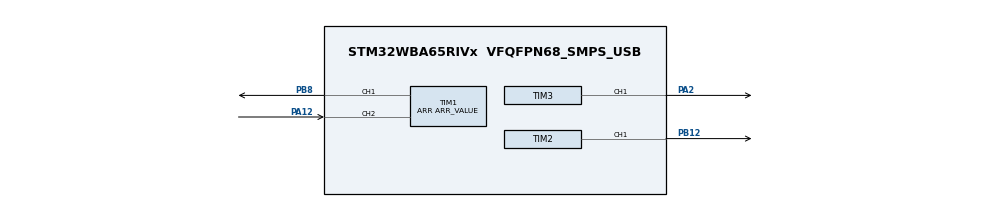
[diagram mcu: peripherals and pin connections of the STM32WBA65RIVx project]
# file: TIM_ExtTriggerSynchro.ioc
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CORTEX_M33_NS.userName=CORTEX_M33
Mcu.Family=STM32WBA
Mcu.Name=STM32WBA65RIVx
Mcu.Package=VFQFPN68_SMPS_USB
NVIC.PriorityGroup=NVIC_PRIORITYGROUP_4
OSC_IN.Mode=HSE-External-Oscillator
OSC_IN.PinAttribute=CortexM33
OSC_IN.Signal=RCC_OSC_IN
OSC_OUT.Mode=HSE-External-Oscillator
OSC_OUT.PinAttribute=CortexM33
OSC_OUT.Signal=RCC_OSC_OUT
PA12.GPIO_PuPd=GPIO_PULLDOWN
PA12.GPIO_Speed=GPIO_SPEED_FREQ_HIGH
PA12.PinAttribute=CortexM33
PA12.Signal=S_TIM1_CH2
PA2.GPIO_PuPd=GPIO_PULLDOWN
PA2.GPIO_Speed=GPIO_SPEED_FREQ_HIGH
PA2.PinAttribute=CortexM33
PA2.Signal=S_TIM3_CH1
PB12.GPIO_PuPd=GPIO_PULLDOWN
PB12.GPIO_Speed=GPIO_SPEED_FREQ_HIGH
PB12.PinAttribute=CortexM33
PB12.Signal=S_TIM2_CH1
PB8.GPIO_PuPd=GPIO_PULLDOWN
PB8.GPIO_Speed=GPIO_SPEED_FREQ_HIGH
PB8.PinAttribute=CortexM33
PB8.Signal=S_TIM1_CH1
ProjectManager.HeapSize=0x200
ProjectManager.StackSize=0x400
ProjectManager.TargetToolchain=EWARM V9.20
RCC.ADCFreq_Value=100000000
RCC.AHB5CLKDivider=DIV4
RCC.AHBFreq_Value=100000000
RCC.APB1Freq_Value=100000000
RCC.APB1TimFreq_Value=100000000
RCC.APB2Freq_Value=100000000
RCC.APB2TimFreq_Value=100000000
RCC.CortexFreq_Value=12500000
RCC.HCLKFreq_Value=100000000
RCC.HSE_VALUE=32000000
RCC.HSI_VALUE=16000000
RCC.LSE_VALUE=32768
RCC.LSI1_VALUE=32000
RCC.LSI2_VALUE=32000
RCC.PLLFRACN=4096
RCC.PLLM=2
RCC.PLLN=12
RCC.PLLSourceVirtual=RCC_PLLSOURCE_HSE
RCC.SYSCLKFreq_VALUE=100000000
RCC.SYSCLKSourceVirtual=RCC_SYSCLKSOURCE_PLLCLK
RCC.VCOOutputFreq_Value=200000000
SH.S_TIM1_CH1.0=TIM1_CH1,Output Compare1 CH1
SH.S_TIM1_CH2.0=TIM1_CH2,TriggerSource_TI2FP2
SH.S_TIM2_CH1.0=TIM2_CH1,Output Compare1 CH1
SH.S_TIM3_CH1.0=TIM3_CH1,Output Compare1 CH1
TIM1.Channel-Output\ Compare1\ CH1=TIM_CHANNEL_1
TIM1.OCMode_1=TIM_OCMODE_TOGGLE
TIM1.PeriodNoDither=ARR_VALUE
TIM1.Prescaler=MASTER_PRESCALER_VALUE
TIM1.TIM_MasterOutputTrigger=TIM_TRGO_ENABLE
TIM1.TIM_MasterOutputTrigger2=TIM_TRGO2_ENABLE
TIM1.TIM_MasterSlaveMode=TIM_MASTERSLAVEMODE_ENABLE
TIM2.Channel-Output\ Compare1\ CH1=TIM_CHANNEL_1
TIM2.OCMode_1=TIM_OCMODE_TOGGLE
TIM2.PeriodNoDither=ARR_VALUE
TIM2.Prescaler=SLAVE_MASTER_PRESCALER_VALUE
TIM2.TIM_MasterOutputTrigger=TIM_TRGO_ENABLE
TIM2.TIM_MasterSlaveMode=TIM_MASTERSLAVEMODE_ENABLE
TIM3.Channel-Output\ Compare1\ CH1=TIM_CHANNEL_1
TIM3.OCMode_1=TIM_OCMODE_TOGGLE
TIM3.PeriodNoDither=ARR_VALUE
TIM3.Prescaler=SLAVE_PRESCALER_VALUE
VP_CORTEX_M33_NS_VS_Hclk.Mode=Hclk_Mode
VP_ICACHE_VS_ICACHE.Mode=DirectMappedCache
VP_PWR_VS_SECSignals.Mode=Security/Privilege
VP_TIM1_VS_ControllerModeGated.Mode=Gated Mode
VP_TIM2_VS_ClockSourceITR.Mode=TriggerSource_ITR0
VP_TIM2_VS_ControllerModeGated.Mode=Gated Mode
VP_TIM3_VS_ClockSourceITR.Mode=TriggerSource_ITR1
VP_TIM3_VS_ControllerModeGated.Mode=Gated Mode
board=custom

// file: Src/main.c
/* USER CODE BEGIN Header */
/**
  ******************************************************************************
  * @file    TIM/TIM_ExtTriggerSynchro/Src/main.c
  * @author  MCD Application Team
  * @brief   This sample code shows how to synchronize TIM peripherals in cascade
  *          mode with an external trigger.
  ******************************************************************************
  * @attention
  *
  * Copyright (c) 2024 STMicroelectronics.
  * All rights reserved.
  *
  * This software is licensed under terms that can be found in the LICENSE file
  * in the root directory of this software component.
  * If no LICENSE file comes with this software, it is provided AS-IS.
  *
  ******************************************************************************
  */
/* USER CODE END Header */
#include "main.h"

TIM_HandleTypeDef htim1;
TIM_HandleTypeDef htim2;
TIM_HandleTypeDef htim3;

void SystemClock_Config(void);
static void MX_GPIO_Init(void);
static void MX_ICACHE_Init(void);
static void MX_TIM1_Init(void);
static void MX_TIM2_Init(void);
static void MX_TIM3_Init(void);

int main(void)
{

  /* USER CODE BEGIN 1 */
  /* STM32WBAxx HAL library initialization:
       - Systick timer is configured by default as source of time base, but user
             can eventually implement his proper time base source (a general purpose
             timer for example or other time source), keeping in mind that Time base
             duration should be kept 1ms since PPP_TIMEOUT_VALUEs are defined and
             handled in milliseconds basis.
       - Set NVIC Group Priority to 4
       - Low Level Initialization
     */
  /* USER CODE END 1 */

  /* MCU Configuration--------------------------------------------------------*/

  /* Reset of all peripherals, Initializes the Flash interface and the Systick. */
  HAL_Init();

  /* Configure the system clock */
  SystemClock_Config();

  /* Initialize all configured peripherals */
  MX_GPIO_Init();
  MX_ICACHE_Init();
  MX_TIM1_Init();
  MX_TIM2_Init();
  MX_TIM3_Init();
  /* USER CODE BEGIN 2 */

  /* Start TIM1 xxxxxxxxxxxxxxxxxxxxxxxxxxxxxxxxxxxxxxxxxxxxxxxxxxxxxxxx */
  /* Start Channel2 in Input Capture */
  if(HAL_TIM_IC_Start(&htim1, TIM_CHANNEL_2) != HAL_OK)
  {
    /* Start Error */
    Error_Handler();
  }
  /* Start the Output Compare */
  if(HAL_TIM_OC_Start(&htim1, TIM_CHANNEL_1) != HAL_OK)
  {
    /* Start Error */
    Error_Handler();
  }

  /* Start TIM2 xxxxxxxxxxxxxxxxxxxxxxxxxxxxxxxxxxxxxxxxxxxxxxxxxxxxxxxx */
  /* Start the Output Compare */
  if(HAL_TIM_OC_Start(&htim2, TIM_CHANNEL_1) != HAL_OK)
  {
    /* Start Error */
    Error_Handler();
  }

  /* Start TIM3 xxxxxxxxxxxxxxxxxxxxxxxxxxxxxxxxxxxxxxxxxxxxxxxxxxxxxxxx */
  /* Start the Output Compare */
  if(HAL_TIM_OC_Start(&htim3, TIM_CHANNEL_1) != HAL_OK)
  {
    /* Start Error */
    Error_Handler();
  }

  /* USER CODE END 2 */

  /* Infinite loop */
  while (1)
  {

  }
}

void SystemClock_Config(void)
{
  RCC_OscInitTypeDef RCC_OscInitStruct = {0};
  RCC_ClkInitTypeDef RCC_ClkInitStruct = {0};

  /** Supply configuration update enable
  */
  HAL_PWREx_ConfigSupply(PWR_LDO_SUPPLY);

  /** Configure the main internal regulator output voltage
  */
  if (HAL_PWREx_ControlVoltageScaling(PWR_REGULATOR_VOLTAGE_SCALE1) != HAL_OK)
  {
    Error_Handler();
  }

  /** Initializes the CPU, AHB and APB busses clocks
  */
  RCC_OscInitStruct.OscillatorType = RCC_OSCILLATORTYPE_HSE;
  RCC_OscInitStruct.HSEState = RCC_HSE_ON;
  RCC_OscInitStruct.HSEDiv = RCC_HSE_DIV1;
  RCC_OscInitStruct.PLL1.PLLState = RCC_PLL_ON;
  RCC_OscInitStruct.PLL1.PLLSource = RCC_PLLSOURCE_HSE;
  RCC_OscInitStruct.PLL1.PLLM = 2;
  RCC_OscInitStruct.PLL1.PLLN = 12;
  RCC_OscInitStruct.PLL1.PLLP = 2;
  RCC_OscInitStruct.PLL1.PLLQ = 2;
  RCC_OscInitStruct.PLL1.PLLR = 2;
  RCC_OscInitStruct.PLL1.PLLFractional = 4096;
  if (HAL_RCC_OscConfig(&RCC_OscInitStruct) != HAL_OK)
  {
    Error_Handler();
  }

  /** Initializes the CPU, AHB and APB busses clocks
  */
  RCC_ClkInitStruct.ClockType = RCC_CLOCKTYPE_HCLK|RCC_CLOCKTYPE_SYSCLK
                              |RCC_CLOCKTYPE_PCLK1|RCC_CLOCKTYPE_PCLK2
                              |RCC_CLOCKTYPE_PCLK7|RCC_CLOCKTYPE_HCLK5;
  RCC_ClkInitStruct.SYSCLKSource = RCC_SYSCLKSOURCE_PLLCLK;
  RCC_ClkInitStruct.AHBCLKDivider = RCC_SYSCLK_DIV1;
  RCC_ClkInitStruct.APB1CLKDivider = RCC_HCLK_DIV1;
  RCC_ClkInitStruct.APB2CLKDivider = RCC_HCLK_DIV1;
  RCC_ClkInitStruct.APB7CLKDivider = RCC_HCLK_DIV1;
  RCC_ClkInitStruct.AHB5_PLL1_CLKDivider = RCC_SYSCLK_PLL1_DIV4;
  RCC_ClkInitStruct.AHB5_HSEHSI_CLKDivider = RCC_SYSCLK_HSEHSI_DIV1;

  if (HAL_RCC_ClockConfig(&RCC_ClkInitStruct, FLASH_LATENCY_3) != HAL_OK)
  {
    Error_Handler();
  }
}

static void MX_ICACHE_Init(void)
{

  /** Enable instruction cache in 1-way (direct mapped cache)
  */
  if (HAL_ICACHE_ConfigAssociativityMode(ICACHE_1WAY) != HAL_OK)
  {
    Error_Handler();
  }
  if (HAL_ICACHE_Enable() != HAL_OK)
  {
    Error_Handler();
  }

}

static void MX_TIM1_Init(void)
{

  TIM_SlaveConfigTypeDef sSlaveConfig = {0};
  TIM_MasterConfigTypeDef sMasterConfig = {0};
  TIM_OC_InitTypeDef sConfigOC = {0};
  TIM_BreakDeadTimeConfigTypeDef sBreakDeadTimeConfig = {0};

  htim1.Instance = TIM1;
  htim1.Init.Prescaler = MASTER_PRESCALER_VALUE;
  htim1.Init.CounterMode = TIM_COUNTERMODE_UP;
  htim1.Init.Period = ARR_VALUE;
  htim1.Init.ClockDivision = TIM_CLOCKDIVISION_DIV1;
  htim1.Init.RepetitionCounter = 0;
  htim1.Init.AutoReloadPreload = TIM_AUTORELOAD_PRELOAD_DISABLE;
  if (HAL_TIM_Base_Init(&htim1) != HAL_OK)
  {
    Error_Handler();
  }
  if (HAL_TIM_OC_Init(&htim1) != HAL_OK)
  {
    Error_Handler();
  }
  sSlaveConfig.SlaveMode = TIM_SLAVEMODE_GATED;
  sSlaveConfig.InputTrigger = TIM_TS_TI2FP2;
  sSlaveConfig.TriggerPolarity = TIM_TRIGGERPOLARITY_RISING;
  sSlaveConfig.TriggerFilter = 0;
  if (HAL_TIM_SlaveConfigSynchro(&htim1, &sSlaveConfig) != HAL_OK)
  {
    Error_Handler();
  }
  sMasterConfig.MasterOutputTrigger = TIM_TRGO_ENABLE;
  sMasterConfig.MasterOutputTrigger2 = TIM_TRGO2_ENABLE;
  sMasterConfig.MasterSlaveMode = TIM_MASTERSLAVEMODE_ENABLE;
  if (HAL_TIMEx_MasterConfigSynchronization(&htim1, &sMasterConfig) != HAL_OK)
  {
    Error_Handler();
  }
  sConfigOC.OCMode = TIM_OCMODE_TOGGLE;
  sConfigOC.Pulse = 0;
  sConfigOC.OCPolarity = TIM_OCPOLARITY_HIGH;
  sConfigOC.OCNPolarity = TIM_OCNPOLARITY_HIGH;
  sConfigOC.OCFastMode = TIM_OCFAST_DISABLE;
  sConfigOC.OCIdleState = TIM_OCIDLESTATE_RESET;
  sConfigOC.OCNIdleState = TIM_OCNIDLESTATE_RESET;
  if (HAL_TIM_OC_ConfigChannel(&htim1, &sConfigOC, TIM_CHANNEL_1) != HAL_OK)
  {
    Error_Handler();
  }
  sBreakDeadTimeConfig.OffStateRunMode = TIM_OSSR_DISABLE;
  sBreakDeadTimeConfig.OffStateIDLEMode = TIM_OSSI_DISABLE;
  sBreakDeadTimeConfig.LockLevel = TIM_LOCKLEVEL_OFF;
  sBreakDeadTimeConfig.DeadTime = 0;
  sBreakDeadTimeConfig.BreakState = TIM_BREAK_DISABLE;
  sBreakDeadTimeConfig.BreakPolarity = TIM_BREAKPOLARITY_HIGH;
  sBreakDeadTimeConfig.BreakFilter = 0;
  sBreakDeadTimeConfig.BreakAFMode = TIM_BREAK_AFMODE_INPUT;
  sBreakDeadTimeConfig.Break2State = TIM_BREAK2_DISABLE;
  sBreakDeadTimeConfig.Break2Polarity = TIM_BREAK2POLARITY_HIGH;
  sBreakDeadTimeConfig.Break2Filter = 0;
  sBreakDeadTimeConfig.Break2AFMode = TIM_BREAK_AFMODE_INPUT;
  sBreakDeadTimeConfig.AutomaticOutput = TIM_AUTOMATICOUTPUT_DISABLE;
  if (HAL_TIMEx_ConfigBreakDeadTime(&htim1, &sBreakDeadTimeConfig) != HAL_OK)
  {
    Error_Handler();
  }
  HAL_TIM_MspPostInit(&htim1);

}

static void MX_TIM2_Init(void)
{

  TIM_SlaveConfigTypeDef sSlaveConfig = {0};
  TIM_MasterConfigTypeDef sMasterConfig = {0};
  TIM_OC_InitTypeDef sConfigOC = {0};

  htim2.Instance = TIM2;
  htim2.Init.Prescaler = SLAVE_MASTER_PRESCALER_VALUE;
  htim2.Init.CounterMode = TIM_COUNTERMODE_UP;
  htim2.Init.Period = ARR_VALUE;
  htim2.Init.ClockDivision = TIM_CLOCKDIVISION_DIV1;
  htim2.Init.AutoReloadPreload = TIM_AUTORELOAD_PRELOAD_DISABLE;
  if (HAL_TIM_Base_Init(&htim2) != HAL_OK)
  {
    Error_Handler();
  }
  if (HAL_TIM_OC_Init(&htim2) != HAL_OK)
  {
    Error_Handler();
  }
  sSlaveConfig.SlaveMode = TIM_SLAVEMODE_GATED;
  sSlaveConfig.InputTrigger = TIM_TS_ITR0;
  if (HAL_TIM_SlaveConfigSynchro(&htim2, &sSlaveConfig) != HAL_OK)
  {
    Error_Handler();
  }
  sMasterConfig.MasterOutputTrigger = TIM_TRGO_ENABLE;
  sMasterConfig.MasterSlaveMode = TIM_MASTERSLAVEMODE_ENABLE;
  if (HAL_TIMEx_MasterConfigSynchronization(&htim2, &sMasterConfig) != HAL_OK)
  {
    Error_Handler();
  }
  sConfigOC.OCMode = TIM_OCMODE_TOGGLE;
  sConfigOC.Pulse = 0;
  sConfigOC.OCPolarity = TIM_OCPOLARITY_HIGH;
  sConfigOC.OCFastMode = TIM_OCFAST_DISABLE;
  if (HAL_TIM_OC_ConfigChannel(&htim2, &sConfigOC, TIM_CHANNEL_1) != HAL_OK)
  {
    Error_Handler();
  }
  HAL_TIM_MspPostInit(&htim2);

}

static void MX_TIM3_Init(void)
{

  TIM_SlaveConfigTypeDef sSlaveConfig = {0};
  TIM_MasterConfigTypeDef sMasterConfig = {0};
  TIM_OC_InitTypeDef sConfigOC = {0};

  htim3.Instance = TIM3;
  htim3.Init.Prescaler = SLAVE_PRESCALER_VALUE;
  htim3.Init.CounterMode = TIM_COUNTERMODE_UP;
  htim3.Init.Period = ARR_VALUE;
  htim3.Init.ClockDivision = TIM_CLOCKDIVISION_DIV1;
  htim3.Init.AutoReloadPreload = TIM_AUTORELOAD_PRELOAD_DISABLE;
  if (HAL_TIM_Base_Init(&htim3) != HAL_OK)
  {
    Error_Handler();
  }
  if (HAL_TIM_OC_Init(&htim3) != HAL_OK)
  {
    Error_Handler();
  }
  sSlaveConfig.SlaveMode = TIM_SLAVEMODE_GATED;
  sSlaveConfig.InputTrigger = TIM_TS_ITR1;
  if (HAL_TIM_SlaveConfigSynchro(&htim3, &sSlaveConfig) != HAL_OK)
  {
    Error_Handler();
  }
  sMasterConfig.MasterOutputTrigger = TIM_TRGO_RESET;
  sMasterConfig.MasterSlaveMode = TIM_MASTERSLAVEMODE_DISABLE;
  if (HAL_TIMEx_MasterConfigSynchronization(&htim3, &sMasterConfig) != HAL_OK)
  {
    Error_Handler();
  }
  sConfigOC.OCMode = TIM_OCMODE_TOGGLE;
  sConfigOC.Pulse = 0;
  sConfigOC.OCPolarity = TIM_OCPOLARITY_HIGH;
  sConfigOC.OCFastMode = TIM_OCFAST_DISABLE;
  if (HAL_TIM_OC_ConfigChannel(&htim3, &sConfigOC, TIM_CHANNEL_1) != HAL_OK)
  {
    Error_Handler();
  }
  HAL_TIM_MspPostInit(&htim3);

}

static void MX_GPIO_Init(void)
{

  /* GPIO Ports Clock Enable */
  __HAL_RCC_GPIOB_CLK_ENABLE();
  __HAL_RCC_GPIOA_CLK_ENABLE();

}

void Error_Handler(void)
{
  while(1)
  {
  }
}
